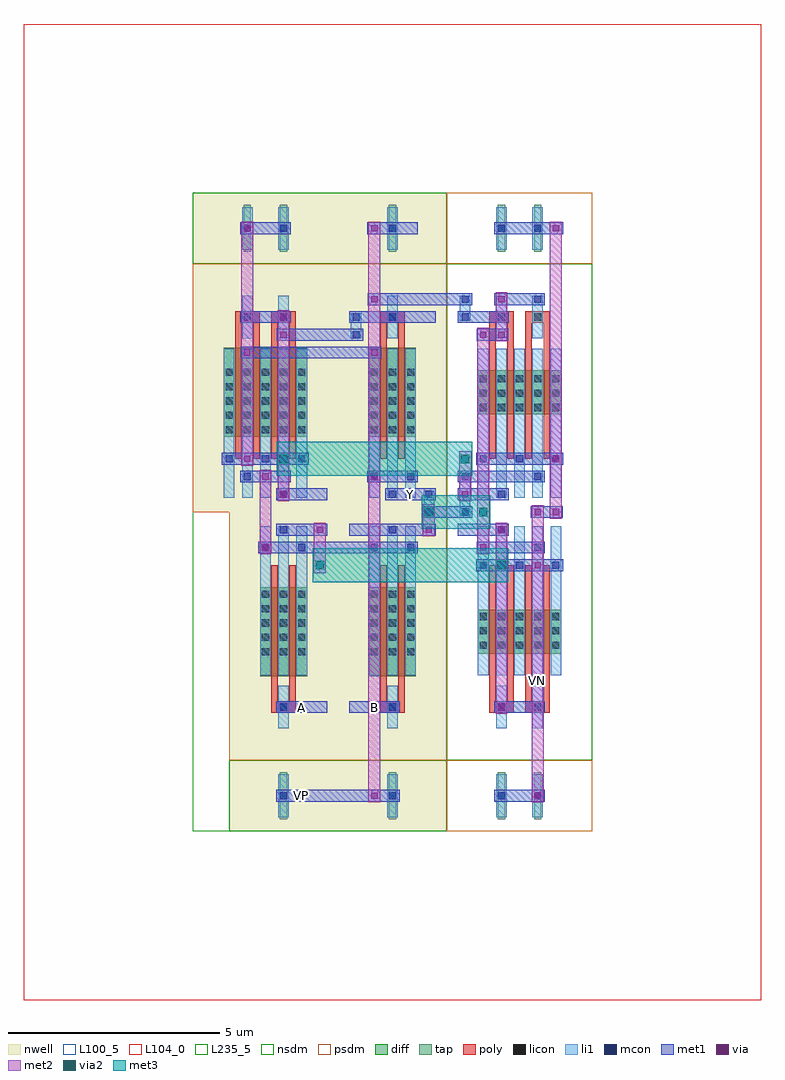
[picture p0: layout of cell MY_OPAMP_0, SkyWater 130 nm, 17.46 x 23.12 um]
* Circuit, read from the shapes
.subckt MY_OPAMP_0 A B VN VP Y
XM1 n1 n1 VN VN sky130_fd_pr__nfet_01v8 w=1.05 l=0.15 m=2
XM2 n2 VP VN VN sky130_fd_pr__nfet_01v8 w=1.05 l=0.15 m=2
XM3 n3 n1 VN VN sky130_fd_pr__nfet_01v8 w=1.05 l=0.15 m=2
XM4 Y n3 VN VN sky130_fd_pr__nfet_01v8 w=1.05 l=0.15 m=2
XM5 n4 n2 VP VP sky130_fd_pr__pfet_01v8 w=2.1 l=0.15 m=2
XM6 n1 A n4 VP sky130_fd_pr__pfet_01v8 w=2.1 l=0.15 m=2
XM7 n2 n2 VP VP sky130_fd_pr__pfet_01v8 w=2.1 l=0.15 m=2
XM8 n3 B n4 VP sky130_fd_pr__pfet_01v8 w=2.1 l=0.15 m=2
XM9 Y n2 VP VP sky130_fd_pr__pfet_01v8 w=2.1 l=0.15 m=2
.ends

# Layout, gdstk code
from math import pi, radians
import gdstk
lib = gdstk.Library(unit=1e-6, precision=1e-09)
def R(c, l, rs):  # rectangles x0, y0, x1, y1
    for r in rs: c.add(gdstk.rectangle(r[:2], r[2:], *l))
def A(c, l, x, y, w, h, nx, ny, dx, dy):  # array of equal rectangles
    R(c, l, [(x+i*dx, y+j*dy, x+i*dx+w, y+j*dy+h) for i in range(nx) for j in range(ny)])
def P(c, l, *ps):  # polygons
    for p in ps: c.add(gdstk.Polygon(p, *l))
nwell = (64, 20)
diff = (65, 20)
tap = (65, 44)
poly = (66, 20)
licon = (66, 44)
li1 = (67, 20)
mcon = (67, 44)
met1 = (68, 20)
via = (68, 44)
met2 = (69, 20)
via2 = (69, 44)
met3 = (70, 20)
nsdm = (93, 44)
psdm = (94, 20)
L100_5 = (100, 5)
L104_0 = (104, 0)
L235_5 = (235, 5)

scm_pmos_7694812_x1_y1_1 = lib.new_cell('SCM_PMOS_7694812_X1_Y1_1678560932_1678560931')
R(scm_pmos_7694812_x1_y1_1, nwell, [(0,0,3.44,7.56)])
R(scm_pmos_7694812_x1_y1_1, diff, [(0.735,1.785,2.705,3.885)])
R(scm_pmos_7694812_x1_y1_1, tap, [(1.205,6.16,1.375,7.28), (2.065,6.16,2.235,7.28)])
A(scm_pmos_7694812_x1_y1_1, poly, 1, 1.26, 0.15, 3.36, 4, 1, 0.43, 0)
R(scm_pmos_7694812_x1_y1_1, poly, [(1,4.485,1.58,4.755), (1.86,4.485,2.44,4.755)])
A(scm_pmos_7694812_x1_y1_1, licon, 0.775, 1.865, 0.17, 0.17, 3, 5, 0.43, 0.34)
A(scm_pmos_7694812_x1_y1_1, licon, 1.635, 1.865, 0.17, 0.17, 3, 5, 0.43, 0.34)
R(scm_pmos_7694812_x1_y1_1, licon, [(1.205,4.535,1.375,4.705), (2.065,4.535,2.235,4.705), (1.205,6.635,1.375,6.805), (2.065,6.635,2.235,6.805)])
A(scm_pmos_7694812_x1_y1_1, li1, 0.735, 0.335, 0.25, 3.53, 5, 1, 0.43, 0)
R(scm_pmos_7694812_x1_y1_1, li1, [(1.165,4.115,1.415,5.125), (2.025,4.115,2.275,5.125), (1.165,6.215,1.415,7.225), (2.025,6.215,2.275,7.225)])
A(scm_pmos_7694812_x1_y1_1, mcon, 0.775, 1.175, 0.17, 0.17, 3, 1, 0.86, 0)
R(scm_pmos_7694812_x1_y1_1, mcon, [(1.205,0.335,1.375,0.505), (2.065,0.755,2.235,0.925), (1.205,4.535,1.375,4.705), (2.065,4.535,2.235,4.705), (1.205,6.635,1.375,6.805), (2.065,6.635,2.235,6.805)])
R(scm_pmos_7694812_x1_y1_1, met1, [(0.26,0.28,1.46,0.56), (1.12,0.7,2.32,0.98), (0.69,1.12,2.75,1.4), (1.12,4.48,2.32,4.76), (1.12,6.58,2.32,6.86)])
R(scm_pmos_7694812_x1_y1_1, via, [(1.215,0.345,1.365,0.495), (2.075,1.185,2.225,1.335), (1.215,4.545,1.365,4.695), (2.075,6.645,2.225,6.795)])
R(scm_pmos_7694812_x1_y1_1, met2, [(1.15,0.26,1.43,4.78), (2.01,1.1,2.29,6.88)])
R(scm_pmos_7694812_x1_y1_1, nsdm, [(0,5.88,3.44,7.56)])
R(scm_pmos_7694812_x1_y1_1, psdm, [(0,0,3.44,5.88)])
R(scm_pmos_7694812_x1_y1_1, L100_5, [(0,0,3.44,7.56)])

pmos_s_19745913_x1_y1_16 = lib.new_cell('PMOS_S_19745913_X1_Y1_1678560931_1678560931')
R(pmos_s_19745913_x1_y1_16, nwell, [(0,0,2.58,7.56)])
R(pmos_s_19745913_x1_y1_16, diff, [(0.735,1.785,1.845,3.885)])
R(pmos_s_19745913_x1_y1_16, tap, [(1.205,6.16,1.375,7.28)])
R(pmos_s_19745913_x1_y1_16, poly, [(1,1.26,1.15,4.62), (1.43,1.26,1.58,4.62), (1,4.485,1.58,4.755)])
A(pmos_s_19745913_x1_y1_16, licon, 0.775, 1.865, 0.17, 0.17, 3, 5, 0.43, 0.34)
R(pmos_s_19745913_x1_y1_16, licon, [(1.205,4.535,1.375,4.705), (1.205,6.635,1.375,6.805)])
A(pmos_s_19745913_x1_y1_16, li1, 0.735, 0.335, 0.25, 3.53, 3, 1, 0.43, 0)
R(pmos_s_19745913_x1_y1_16, li1, [(1.165,4.115,1.415,5.125), (1.165,6.215,1.415,7.225)])
R(pmos_s_19745913_x1_y1_16, mcon, [(1.205,0.335,1.375,0.505), (0.775,0.755,0.945,0.925), (1.635,0.755,1.805,0.925), (1.205,4.535,1.375,4.705), (1.205,6.635,1.375,6.805)])
R(pmos_s_19745913_x1_y1_16, met1, [(0.26,0.28,1.46,0.56), (0.69,0.7,1.89,0.98), (0.26,4.48,1.46,4.76), (0.69,6.58,1.89,6.86)])
R(pmos_s_19745913_x1_y1_16, via, [(1.645,0.765,1.795,0.915), (1.645,6.645,1.795,6.795)])
R(pmos_s_19745913_x1_y1_16, met2, [(1.58,0.68,1.86,6.88)])
R(pmos_s_19745913_x1_y1_16, nsdm, [(0,5.88,2.58,7.56)])
R(pmos_s_19745913_x1_y1_16, psdm, [(0,0,2.58,5.88)])
R(pmos_s_19745913_x1_y1_16, L100_5, [(0,0,2.58,7.56)])

cmb_pmos_2_68553526_0_0_ = lib.new_cell('CMB_PMOS_2_68553526_0_0_1678560931')
R(cmb_pmos_2_68553526_0_0_, li1, [(2.025,4.115,2.275,4.285), (2.025,4.115,2.275,4.285), (2.025,4.2,2.275,4.62), (2.025,4.535,2.275,4.705), (2.025,4.535,2.275,4.705)])
R(cmb_pmos_2_68553526_0_0_, mcon, [(2.065,4.115,2.235,4.285), (2.065,4.115,2.235,4.285), (2.065,4.535,2.235,4.705), (2.065,4.535,2.235,4.705)])
R(cmb_pmos_2_68553526_0_0_, met1, [(1.56,3.64,1.88,3.92), (1.56,3.64,1.88,3.92), (1.72,3.64,4.73,3.92), (4.57,3.64,4.89,3.92), (4.57,3.64,4.89,3.92), (1.98,4.06,2.32,4.34), (1.98,4.06,2.32,4.34), (2.15,4.06,3.87,4.34), (3.71,4.06,4.03,4.34), (3.71,4.06,4.03,4.34), (1.29,4.48,2.15,4.76), (1.98,4.48,2.32,4.76), (1.98,4.48,2.32,4.76)])
P(cmb_pmos_2_68553526_0_0_, met1, [(0,0),(0,0),(0,0),(0,0)],
  [(0,0),(0,0),(0,0),(0,0)],
  [(0,0),(0,0),(0,0),(0,0)])
R(cmb_pmos_2_68553526_0_0_, via, [(1.645,3.705,1.795,3.855), (1.645,3.705,1.795,3.855), (4.655,3.705,4.805,3.855), (4.655,3.705,4.805,3.855), (3.795,4.125,3.945,4.275), (3.795,4.125,3.945,4.275)])
R(cmb_pmos_2_68553526_0_0_, met2, [(1.58,3.62,1.86,3.94), (1.58,3.62,1.86,3.94), (4.59,3.62,4.87,3.94), (4.59,3.62,4.87,3.94), (3.73,4.04,4.01,4.36), (3.73,4.04,4.01,4.36)])
P(cmb_pmos_2_68553526_0_0_, met2, [(0,0),(0,0),(0,0),(0,0)],
  [(0,0),(0,0),(0,0),(0,0)],
  [(0,0),(0,0),(0,0),(0,0)])
R(cmb_pmos_2_68553526_0_0_, L235_5, [(0,0,6.02,7.56)])
cmb_pmos_2_68553526_0_0_.add(gdstk.Reference(scm_pmos_7694812_x1_y1_1, (2.58,0)))
cmb_pmos_2_68553526_0_0_.add(gdstk.Reference(pmos_s_19745913_x1_y1_16, (0,0)))

scm_nmos_43308780_x1_y1_ = lib.new_cell('SCM_NMOS_43308780_X1_Y1_1678560934')
R(scm_nmos_43308780_x1_y1_, diff, [(0.735,2.31,2.705,3.36)])
R(scm_nmos_43308780_x1_y1_, tap, [(1.205,6.16,1.375,7.28), (2.065,6.16,2.235,7.28)])
A(scm_nmos_43308780_x1_y1_, poly, 1, 1.26, 0.15, 3.36, 4, 1, 0.43, 0)
R(scm_nmos_43308780_x1_y1_, poly, [(1,4.485,1.58,4.755), (1.86,4.485,2.44,4.755)])
A(scm_nmos_43308780_x1_y1_, licon, 0.775, 2.39, 0.17, 0.17, 3, 3, 0.43, 0.34)
A(scm_nmos_43308780_x1_y1_, licon, 1.635, 2.39, 0.17, 0.17, 3, 3, 0.43, 0.34)
R(scm_nmos_43308780_x1_y1_, licon, [(1.205,4.535,1.375,4.705), (2.065,4.535,2.235,4.705), (1.205,6.635,1.375,6.805), (2.065,6.635,2.235,6.805)])
A(scm_nmos_43308780_x1_y1_, li1, 0.735, 0.335, 0.25, 3.53, 5, 1, 0.43, 0)
R(scm_nmos_43308780_x1_y1_, li1, [(1.165,4.115,1.415,5.125), (2.025,4.115,2.275,5.125), (1.165,6.215,1.415,7.225), (2.025,6.215,2.275,7.225)])
A(scm_nmos_43308780_x1_y1_, mcon, 0.775, 1.175, 0.17, 0.17, 3, 1, 0.86, 0)
R(scm_nmos_43308780_x1_y1_, mcon, [(1.205,0.335,1.375,0.505), (2.065,0.755,2.235,0.925), (1.205,4.535,1.375,4.705), (2.065,4.535,2.235,4.705), (1.205,6.635,1.375,6.805), (2.065,6.635,2.235,6.805)])
R(scm_nmos_43308780_x1_y1_, met1, [(0.26,0.28,1.46,0.56), (1.12,0.7,2.32,0.98), (0.69,1.12,2.75,1.4), (1.12,4.48,2.32,4.76), (1.12,6.58,2.32,6.86)])
R(scm_nmos_43308780_x1_y1_, via, [(1.215,0.345,1.365,0.495), (2.075,1.185,2.225,1.335), (1.215,4.545,1.365,4.695), (2.075,6.645,2.225,6.795)])
R(scm_nmos_43308780_x1_y1_, met2, [(1.15,0.26,1.43,4.78), (2.01,1.1,2.29,6.88)])
R(scm_nmos_43308780_x1_y1_, nsdm, [(0,0,3.44,5.88)])
R(scm_nmos_43308780_x1_y1_, psdm, [(0,5.88,3.44,7.56)])
R(scm_nmos_43308780_x1_y1_, L100_5, [(0,0,3.44,7.56)])

dp_nmos_95268315_x1_y1_1 = lib.new_cell('DP_NMOS_95268315_X1_Y1_1678560932')
R(dp_nmos_95268315_x1_y1_1, diff, [(0.735,2.31,2.705,3.36)])
R(dp_nmos_95268315_x1_y1_1, tap, [(1.205,6.16,1.375,7.28), (2.065,6.16,2.235,7.28)])
A(dp_nmos_95268315_x1_y1_1, poly, 1, 1.26, 0.15, 3.36, 4, 1, 0.43, 0)
R(dp_nmos_95268315_x1_y1_1, poly, [(1,4.485,1.58,4.755), (1.86,4.485,2.44,4.755)])
A(dp_nmos_95268315_x1_y1_1, licon, 0.775, 2.39, 0.17, 0.17, 3, 3, 0.43, 0.34)
A(dp_nmos_95268315_x1_y1_1, licon, 1.635, 2.39, 0.17, 0.17, 3, 3, 0.43, 0.34)
R(dp_nmos_95268315_x1_y1_1, licon, [(1.205,4.535,1.375,4.705), (2.065,4.535,2.235,4.705), (1.205,6.635,1.375,6.805), (2.065,6.635,2.235,6.805)])
A(dp_nmos_95268315_x1_y1_1, li1, 0.735, 0.335, 0.25, 3.53, 5, 1, 0.43, 0)
R(dp_nmos_95268315_x1_y1_1, li1, [(1.165,4.115,1.415,5.125), (2.025,4.115,2.275,5.125), (1.165,6.215,1.415,7.225), (2.025,6.215,2.275,7.225)])
A(dp_nmos_95268315_x1_y1_1, mcon, 0.775, 1.175, 0.17, 0.17, 3, 1, 0.86, 0)
R(dp_nmos_95268315_x1_y1_1, mcon, [(1.205,0.335,1.375,0.505), (2.065,0.755,2.235,0.925), (1.205,4.535,1.375,4.705), (2.065,4.955,2.235,5.125), (1.205,6.635,1.375,6.805), (2.065,6.635,2.235,6.805)])
R(dp_nmos_95268315_x1_y1_1, met1, [(0.26,0.28,1.46,0.56), (1.12,0.7,2.32,0.98), (0.69,1.12,2.75,1.4), (0.26,4.48,1.46,4.76), (1.12,4.9,2.32,5.18), (1.12,6.58,2.75,6.86)])
R(dp_nmos_95268315_x1_y1_1, via, [(2.505,1.185,2.655,1.335), (2.505,6.645,2.655,6.795)])
R(dp_nmos_95268315_x1_y1_1, met2, [(2.44,1.1,2.72,6.88)])
R(dp_nmos_95268315_x1_y1_1, nsdm, [(0,0,3.44,5.88)])
R(dp_nmos_95268315_x1_y1_1, psdm, [(0,5.88,3.44,7.56)])
R(dp_nmos_95268315_x1_y1_1, L100_5, [(0,0,3.44,7.56)])

pmos_4t_31631261_x1_y1_1 = lib.new_cell('PMOS_4T_31631261_X1_Y1_1678560933')
R(pmos_4t_31631261_x1_y1_1, nwell, [(0,0,2.58,7.56)])
R(pmos_4t_31631261_x1_y1_1, diff, [(0.735,1.785,1.845,3.885)])
R(pmos_4t_31631261_x1_y1_1, tap, [(1.205,6.16,1.375,7.28)])
R(pmos_4t_31631261_x1_y1_1, poly, [(1,1.26,1.15,4.62), (1.43,1.26,1.58,4.62), (1,4.485,1.58,4.755)])
A(pmos_4t_31631261_x1_y1_1, licon, 0.775, 1.865, 0.17, 0.17, 3, 5, 0.43, 0.34)
R(pmos_4t_31631261_x1_y1_1, licon, [(1.205,4.535,1.375,4.705), (1.205,6.635,1.375,6.805)])
A(pmos_4t_31631261_x1_y1_1, li1, 0.735, 0.335, 0.25, 3.53, 3, 1, 0.43, 0)
R(pmos_4t_31631261_x1_y1_1, li1, [(1.165,4.115,1.415,5.125), (1.165,6.215,1.415,7.225)])
R(pmos_4t_31631261_x1_y1_1, mcon, [(1.205,0.335,1.375,0.505), (0.775,0.755,0.945,0.925), (1.635,0.755,1.805,0.925), (1.205,4.535,1.375,4.705), (1.205,6.635,1.375,6.805)])
R(pmos_4t_31631261_x1_y1_1, met1, [(0.26,0.28,1.46,0.56), (0.69,0.7,1.89,0.98), (0.26,4.48,1.46,4.76), (0.26,6.58,1.46,6.86)])
R(pmos_4t_31631261_x1_y1_1, nsdm, [(0,5.88,2.58,7.56)])
R(pmos_4t_31631261_x1_y1_1, psdm, [(0,0,2.58,5.88)])
R(pmos_4t_31631261_x1_y1_1, L100_5, [(0,0,2.58,7.56)])

my_opamp_0 = lib.new_cell('MY_OPAMP_0')
R(my_opamp_0, li1, [(5.465,7.475,5.715,7.645), (5.465,7.475,5.715,7.645), (6.325,7.475,6.575,7.645), (6.325,7.475,6.575,7.645), (5.465,7.56,5.715,7.98), (6.325,7.56,6.575,8.4), (5.465,7.895,5.715,8.065), (5.465,7.895,5.715,8.065), (6.325,8.315,6.575,8.485), (6.325,8.315,6.575,8.485), (6.325,12.095,6.575,12.265), (6.325,12.095,6.575,12.265), (6.325,12.18,6.575,12.6), (6.325,12.515,6.575,12.685), (6.325,12.515,6.575,12.685)])
P(my_opamp_0, li1, [(0,0),(0,0),(0,0),(0,0)])
R(my_opamp_0, mcon, [(5.505,7.475,5.675,7.645), (5.505,7.475,5.675,7.645), (6.365,7.475,6.535,7.645), (6.365,7.475,6.535,7.645), (5.505,7.895,5.675,8.065), (5.505,7.895,5.675,8.065), (6.365,8.315,6.535,8.485), (6.365,8.315,6.535,8.485), (6.365,12.095,6.535,12.265), (6.365,12.095,6.535,12.265), (6.365,12.515,6.535,12.685), (6.365,12.515,6.535,12.685)])
R(my_opamp_0, met1, [(3.01,0.7,3.87,0.98), (4.14,0.7,4.46,0.98), (4.14,0.7,4.46,0.98), (4.14,0.7,4.46,0.98), (4.14,0.7,4.46,0.98), (1.56,6.58,1.88,6.86), (1.56,6.58,1.88,6.86), (1.56,6.58,1.88,6.86), (1.56,6.58,1.88,6.86), (2.58,6.58,4.3,6.86), (6.72,6.58,7.04,6.86), (6.72,6.58,7.04,6.86), (6.72,6.58,7.04,6.86), (6.72,6.58,7.04,6.86), (6.88,6.58,7.31,6.86), (2.85,7,3.17,7.28), (2.85,7,3.17,7.28), (4.73,7,5.59,7.28), (5.43,7,5.75,7.28), (5.43,7,5.75,7.28), (5.43,7,5.75,7.28), (5.43,7,5.75,7.28), (5.42,7.42,5.76,7.7), (5.42,7.42,5.76,7.7), (5.59,7.42,6.45,7.7), (6.28,7.42,6.62,7.7), (6.28,7.42,6.62,7.7), (8.01,7.42,8.33,7.7), (8.01,7.42,8.33,7.7), (8.17,7.42,8.6,7.7), (8.44,7.42,8.76,7.7), (8.44,7.42,8.76,7.7), (5.42,7.84,5.76,8.12), (5.42,7.84,5.76,8.12), (6.29,7.84,6.61,8.12), (6.29,7.84,6.61,8.12), (1.56,8.26,1.88,8.54), (1.56,8.26,1.88,8.54), (1.56,8.26,1.88,8.54), (1.56,8.26,1.88,8.54), (6.28,8.26,6.62,8.54), (6.28,8.26,6.62,8.54), (6.45,8.26,7.31,8.54), (6.72,11.62,7.04,11.9), (6.72,11.62,7.04,11.9), (6.88,11.62,7.31,11.9), (7.15,11.62,7.47,11.9), (7.15,11.62,7.47,11.9), (6.28,12.04,6.62,12.32), (6.28,12.04,6.62,12.32), (4.14,12.46,4.46,12.74), (4.14,12.46,4.46,12.74), (4.3,12.46,6.45,12.74), (6.28,12.46,6.62,12.74), (6.28,12.46,6.62,12.74), (7.15,12.46,7.47,12.74), (7.15,12.46,7.47,12.74)])
P(my_opamp_0, met1, [(0,0),(0,0),(0,0),(0,0)],
  [(0,0),(0,0),(0,0),(0,0)],
  [(0,0),(0,0),(0,0),(0,0)],
  [(0,0),(0,0),(0,0),(0,0)],
  [(0,0),(0,0),(0,0),(0,0)],
  [(0,0),(0,0),(0,0),(0,0)],
  [(0,0),(0,0),(0,0),(0,0)],
  [(0,0),(0,0),(0,0),(0,0)],
  [(0,0),(0,0),(0,0),(0,0)],
  [(0,0),(0,0),(0,0),(0,0)],
  [(0,0),(0,0),(0,0),(0,0)],
  [(0,0),(0,0),(0,0),(0,0)],
  [(0,0),(0,0),(0,0),(0,0)],
  [(0,0),(0,0),(0,0),(0,0)],
  [(0,0),(0,0),(0,0),(0,0)],
  [(0,0),(0,0),(0,0),(0,0)],
  [(0,0),(0,0),(0,0),(0,0)],
  [(0,0),(0,0),(0,0),(0,0)],
  [(0,0),(0,0),(0,0),(0,0)],
  [(0,0),(0,0),(0,0),(0,0)],
  [(0,0),(0,0),(0,0),(0,0)],
  [(0,0),(0,0),(0,0),(0,0)],
  [(0,0),(0,0),(0,0),(0,0)])
R(my_opamp_0, via, [(4.225,0.765,4.375,0.915), (4.225,0.765,4.375,0.915), (4.225,0.765,4.375,0.915), (4.225,0.765,4.375,0.915), (1.645,6.645,1.795,6.795), (1.645,6.645,1.795,6.795), (1.645,6.645,1.795,6.795), (1.645,6.645,1.795,6.795), (6.805,6.645,6.955,6.795), (6.805,6.645,6.955,6.795), (6.805,6.645,6.955,6.795), (6.805,6.645,6.955,6.795), (2.935,7.065,3.085,7.215), (2.935,7.065,3.085,7.215), (5.515,7.065,5.665,7.215), (5.515,7.065,5.665,7.215), (5.515,7.065,5.665,7.215), (5.515,7.065,5.665,7.215), (8.095,7.485,8.245,7.635), (8.095,7.485,8.245,7.635), (8.525,7.485,8.675,7.635), (8.525,7.485,8.675,7.635), (6.375,7.905,6.525,8.055), (6.375,7.905,6.525,8.055), (1.645,8.325,1.795,8.475), (1.645,8.325,1.795,8.475), (1.645,8.325,1.795,8.475), (1.645,8.325,1.795,8.475), (6.805,11.685,6.955,11.835), (6.805,11.685,6.955,11.835), (7.235,11.685,7.385,11.835), (7.235,11.685,7.385,11.835), (4.225,12.525,4.375,12.675), (4.225,12.525,4.375,12.675), (7.235,12.525,7.385,12.675), (7.235,12.525,7.385,12.675)])
R(my_opamp_0, met2, [(4.16,0.68,4.44,1), (4.16,0.68,4.44,1), (4.16,0.68,4.44,1), (4.16,0.68,4.44,1), (4.16,0.84,4.44,8.4), (2.87,6.115,3.15,6.485), (2.87,6.115,3.15,6.485), (7.17,6.115,7.45,6.485), (7.17,6.115,7.45,6.485), (2.87,6.3,3.15,7.14), (8.03,6.3,8.31,7.56), (1.58,6.56,1.86,6.88), (1.58,6.56,1.86,6.88), (1.58,6.56,1.86,6.88), (1.58,6.56,1.86,6.88), (6.74,6.56,7.02,6.88), (6.74,6.56,7.02,6.88), (6.74,6.56,7.02,6.88), (6.74,6.56,7.02,6.88), (1.58,6.72,1.86,8.4), (6.74,6.72,7.02,7.56), (2.87,6.98,3.15,7.3), (2.87,6.98,3.15,7.3), (5.45,6.98,5.73,7.3), (5.45,6.98,5.73,7.3), (5.45,6.98,5.73,7.3), (5.45,6.98,5.73,7.3), (5.45,7.14,5.73,7.56), (5.45,7.375,5.73,7.745), (5.45,7.375,5.73,7.745), (5.45,7.375,5.73,7.745), (5.45,7.375,5.73,7.745), (6.74,7.375,7.02,7.745), (6.74,7.375,7.02,7.745), (6.74,7.375,7.02,7.745), (6.74,7.375,7.02,7.745), (8.03,7.4,8.31,7.72), (8.03,7.4,8.31,7.72), (8.46,7.4,8.74,7.72), (8.46,7.4,8.74,7.72), (6.74,7.56,7.02,11.76), (8.46,7.56,8.74,8.82), (6.31,7.82,6.59,8.14), (6.31,7.82,6.59,8.14), (6.31,7.98,6.59,8.82), (1.58,8.24,1.86,8.56), (1.58,8.24,1.86,8.56), (1.58,8.24,1.86,8.56), (1.58,8.24,1.86,8.56), (2.01,8.635,2.29,9.005), (2.01,8.635,2.29,9.005), (6.31,8.635,6.59,9.005), (6.31,8.635,6.59,9.005), (6.74,11.6,7.02,11.92), (6.74,11.6,7.02,11.92), (7.17,11.6,7.45,11.92), (7.17,11.6,7.45,11.92), (7.17,11.76,7.45,12.6), (4.16,12.44,4.44,12.76), (4.16,12.44,4.44,12.76), (7.17,12.44,7.45,12.76), (7.17,12.44,7.45,12.76)])
P(my_opamp_0, met2, [(0,0),(0,0),(0,0),(0,0)],
  [(0,0),(0,0),(0,0),(0,0)],
  [(0,0),(0,0),(0,0),(0,0)],
  [(0,0),(0,0),(0,0),(0,0)],
  [(0,0),(0,0),(0,0),(0,0)],
  [(0,0),(0,0),(0,0),(0,0)],
  [(0,0),(0,0),(0,0),(0,0)],
  [(0,0),(0,0),(0,0),(0,0)],
  [(0,0),(0,0),(0,0),(0,0)],
  [(0,0),(0,0),(0,0),(0,0)])
R(my_opamp_0, via2, [(2.91,6.2,3.11,6.4), (2.91,6.2,3.11,6.4), (7.21,6.2,7.41,6.4), (7.21,6.2,7.41,6.4), (5.49,7.46,5.69,7.66), (5.49,7.46,5.69,7.66), (5.49,7.46,5.69,7.66), (5.49,7.46,5.69,7.66), (6.78,7.46,6.98,7.66), (6.78,7.46,6.98,7.66), (6.78,7.46,6.98,7.66), (6.78,7.46,6.98,7.66), (2.05,8.72,2.25,8.92), (2.05,8.72,2.25,8.92), (6.35,8.72,6.55,8.92), (6.35,8.72,6.55,8.92)])
R(my_opamp_0, met3, [(2.845,5.9,3.175,6.7), (2.845,5.9,3.175,6.7), (3.01,5.9,7.31,6.7), (7.145,5.9,7.475,6.7), (7.145,5.9,7.475,6.7), (5.425,7.16,5.755,7.96), (5.425,7.16,5.755,7.96), (5.425,7.16,5.755,7.96), (5.425,7.16,5.755,7.96), (5.59,7.16,6.88,7.96), (6.715,7.16,7.045,7.96), (6.715,7.16,7.045,7.96), (6.715,7.16,7.045,7.96), (6.715,7.16,7.045,7.96), (1.985,8.42,2.315,9.22), (1.985,8.42,2.315,9.22), (2.15,8.42,6.45,9.22), (6.285,8.42,6.615,9.22), (6.285,8.42,6.615,9.22)])
R(my_opamp_0, L104_0, [(-4,-4,13.46,19.12)])
R(my_opamp_0, L235_5, [(0,0,9.46,15.12)])
my_opamp_0.add(gdstk.Reference(cmb_pmos_2_68553526_0_0_, (6.02,7.56), rotation=pi, x_reflection=True))
my_opamp_0.add(gdstk.Reference(scm_nmos_43308780_x1_y1_, (6.02,7.56), x_reflection=True))
my_opamp_0.add(gdstk.Reference(dp_nmos_95268315_x1_y1_1, (6.02,7.56)))
my_opamp_0.add(gdstk.Reference(pmos_4t_31631261_x1_y1_1, (3.44,7.56), rotation=pi))
my_opamp_0.add(gdstk.Reference(pmos_4t_31631261_x1_y1_1, (3.44,7.56), x_reflection=True))
my_opamp_0.add(gdstk.Label('Y', (5.16,7.98), layer=68, texttype=5))
my_opamp_0.add(gdstk.Label('VP', (2.58,0.84), layer=68, texttype=5))
my_opamp_0.add(gdstk.Label('VN', (8.17,3.57), layer=69, texttype=5))
my_opamp_0.add(gdstk.Label('A', (2.58,2.94), layer=68, texttype=5))
my_opamp_0.add(gdstk.Label('B', (4.3,2.94), layer=68, texttype=5))

lib.write_gds('MY_OPAMP_0.gds')
